VERSION 5.7 ;
BUSBITCHARS "[]" ;
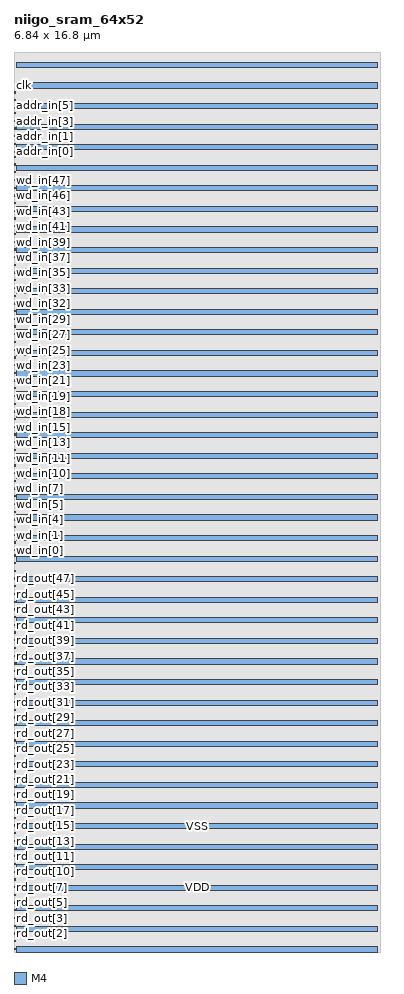
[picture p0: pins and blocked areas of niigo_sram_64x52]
MACRO niigo_sram_64x52
  FOREIGN niigo_sram_64x52 0 0 ;
  SYMMETRY X Y R90 ;
  SIZE 6.840 BY 16.800 ;
  CLASS BLOCK ;
  PIN rd_out[0]
    DIRECTION OUTPUT ;
    USE SIGNAL ;
    SHAPE ABUTMENT ;
    PORT
      LAYER M4 ;
      RECT 0.000 0.048 0.024 0.072 ;
    END
  END rd_out[0]
  PIN rd_out[1]
    DIRECTION OUTPUT ;
    USE SIGNAL ;
    SHAPE ABUTMENT ;
    PORT
      LAYER M4 ;
      RECT 0.000 0.192 0.024 0.216 ;
    END
  END rd_out[1]
  PIN rd_out[2]
    DIRECTION OUTPUT ;
    USE SIGNAL ;
    SHAPE ABUTMENT ;
    PORT
      LAYER M4 ;
      RECT 0.000 0.336 0.024 0.360 ;
    END
  END rd_out[2]
  PIN rd_out[3]
    DIRECTION OUTPUT ;
    USE SIGNAL ;
    SHAPE ABUTMENT ;
    PORT
      LAYER M4 ;
      RECT 0.000 0.480 0.024 0.504 ;
    END
  END rd_out[3]
  PIN rd_out[4]
    DIRECTION OUTPUT ;
    USE SIGNAL ;
    SHAPE ABUTMENT ;
    PORT
      LAYER M4 ;
      RECT 0.000 0.624 0.024 0.648 ;
    END
  END rd_out[4]
  PIN rd_out[5]
    DIRECTION OUTPUT ;
    USE SIGNAL ;
    SHAPE ABUTMENT ;
    PORT
      LAYER M4 ;
      RECT 0.000 0.768 0.024 0.792 ;
    END
  END rd_out[5]
  PIN rd_out[6]
    DIRECTION OUTPUT ;
    USE SIGNAL ;
    SHAPE ABUTMENT ;
    PORT
      LAYER M4 ;
      RECT 0.000 0.912 0.024 0.936 ;
    END
  END rd_out[6]
  PIN rd_out[7]
    DIRECTION OUTPUT ;
    USE SIGNAL ;
    SHAPE ABUTMENT ;
    PORT
      LAYER M4 ;
      RECT 0.000 1.056 0.024 1.080 ;
    END
  END rd_out[7]
  PIN rd_out[8]
    DIRECTION OUTPUT ;
    USE SIGNAL ;
    SHAPE ABUTMENT ;
    PORT
      LAYER M4 ;
      RECT 0.000 1.200 0.024 1.224 ;
    END
  END rd_out[8]
  PIN rd_out[9]
    DIRECTION OUTPUT ;
    USE SIGNAL ;
    SHAPE ABUTMENT ;
    PORT
      LAYER M4 ;
      RECT 0.000 1.344 0.024 1.368 ;
    END
  END rd_out[9]
  PIN rd_out[10]
    DIRECTION OUTPUT ;
    USE SIGNAL ;
    SHAPE ABUTMENT ;
    PORT
      LAYER M4 ;
      RECT 0.000 1.488 0.024 1.512 ;
    END
  END rd_out[10]
  PIN rd_out[11]
    DIRECTION OUTPUT ;
    USE SIGNAL ;
    SHAPE ABUTMENT ;
    PORT
      LAYER M4 ;
      RECT 0.000 1.632 0.024 1.656 ;
    END
  END rd_out[11]
  PIN rd_out[12]
    DIRECTION OUTPUT ;
    USE SIGNAL ;
    SHAPE ABUTMENT ;
    PORT
      LAYER M4 ;
      RECT 0.000 1.776 0.024 1.800 ;
    END
  END rd_out[12]
  PIN rd_out[13]
    DIRECTION OUTPUT ;
    USE SIGNAL ;
    SHAPE ABUTMENT ;
    PORT
      LAYER M4 ;
      RECT 0.000 1.920 0.024 1.944 ;
    END
  END rd_out[13]
  PIN rd_out[14]
    DIRECTION OUTPUT ;
    USE SIGNAL ;
    SHAPE ABUTMENT ;
    PORT
      LAYER M4 ;
      RECT 0.000 2.064 0.024 2.088 ;
    END
  END rd_out[14]
  PIN rd_out[15]
    DIRECTION OUTPUT ;
    USE SIGNAL ;
    SHAPE ABUTMENT ;
    PORT
      LAYER M4 ;
      RECT 0.000 2.208 0.024 2.232 ;
    END
  END rd_out[15]
  PIN rd_out[16]
    DIRECTION OUTPUT ;
    USE SIGNAL ;
    SHAPE ABUTMENT ;
    PORT
      LAYER M4 ;
      RECT 0.000 2.352 0.024 2.376 ;
    END
  END rd_out[16]
  PIN rd_out[17]
    DIRECTION OUTPUT ;
    USE SIGNAL ;
    SHAPE ABUTMENT ;
    PORT
      LAYER M4 ;
      RECT 0.000 2.496 0.024 2.520 ;
    END
  END rd_out[17]
  PIN rd_out[18]
    DIRECTION OUTPUT ;
    USE SIGNAL ;
    SHAPE ABUTMENT ;
    PORT
      LAYER M4 ;
      RECT 0.000 2.640 0.024 2.664 ;
    END
  END rd_out[18]
  PIN rd_out[19]
    DIRECTION OUTPUT ;
    USE SIGNAL ;
    SHAPE ABUTMENT ;
    PORT
      LAYER M4 ;
      RECT 0.000 2.784 0.024 2.808 ;
    END
  END rd_out[19]
  PIN rd_out[20]
    DIRECTION OUTPUT ;
    USE SIGNAL ;
    SHAPE ABUTMENT ;
    PORT
      LAYER M4 ;
      RECT 0.000 2.928 0.024 2.952 ;
    END
  END rd_out[20]
  PIN rd_out[21]
    DIRECTION OUTPUT ;
    USE SIGNAL ;
    SHAPE ABUTMENT ;
    PORT
      LAYER M4 ;
      RECT 0.000 3.072 0.024 3.096 ;
    END
  END rd_out[21]
  PIN rd_out[22]
    DIRECTION OUTPUT ;
    USE SIGNAL ;
    SHAPE ABUTMENT ;
    PORT
      LAYER M4 ;
      RECT 0.000 3.216 0.024 3.240 ;
    END
  END rd_out[22]
  PIN rd_out[23]
    DIRECTION OUTPUT ;
    USE SIGNAL ;
    SHAPE ABUTMENT ;
    PORT
      LAYER M4 ;
      RECT 0.000 3.360 0.024 3.384 ;
    END
  END rd_out[23]
  PIN rd_out[24]
    DIRECTION OUTPUT ;
    USE SIGNAL ;
    SHAPE ABUTMENT ;
    PORT
      LAYER M4 ;
      RECT 0.000 3.504 0.024 3.528 ;
    END
  END rd_out[24]
  PIN rd_out[25]
    DIRECTION OUTPUT ;
    USE SIGNAL ;
    SHAPE ABUTMENT ;
    PORT
      LAYER M4 ;
      RECT 0.000 3.648 0.024 3.672 ;
    END
  END rd_out[25]
  PIN rd_out[26]
    DIRECTION OUTPUT ;
    USE SIGNAL ;
    SHAPE ABUTMENT ;
    PORT
      LAYER M4 ;
      RECT 0.000 3.792 0.024 3.816 ;
    END
  END rd_out[26]
  PIN rd_out[27]
    DIRECTION OUTPUT ;
    USE SIGNAL ;
    SHAPE ABUTMENT ;
    PORT
      LAYER M4 ;
      RECT 0.000 3.936 0.024 3.960 ;
    END
  END rd_out[27]
  PIN rd_out[28]
    DIRECTION OUTPUT ;
    USE SIGNAL ;
    SHAPE ABUTMENT ;
    PORT
      LAYER M4 ;
      RECT 0.000 4.080 0.024 4.104 ;
    END
  END rd_out[28]
  PIN rd_out[29]
    DIRECTION OUTPUT ;
    USE SIGNAL ;
    SHAPE ABUTMENT ;
    PORT
      LAYER M4 ;
      RECT 0.000 4.224 0.024 4.248 ;
    END
  END rd_out[29]
  PIN rd_out[30]
    DIRECTION OUTPUT ;
    USE SIGNAL ;
    SHAPE ABUTMENT ;
    PORT
      LAYER M4 ;
      RECT 0.000 4.368 0.024 4.392 ;
    END
  END rd_out[30]
  PIN rd_out[31]
    DIRECTION OUTPUT ;
    USE SIGNAL ;
    SHAPE ABUTMENT ;
    PORT
      LAYER M4 ;
      RECT 0.000 4.512 0.024 4.536 ;
    END
  END rd_out[31]
  PIN rd_out[32]
    DIRECTION OUTPUT ;
    USE SIGNAL ;
    SHAPE ABUTMENT ;
    PORT
      LAYER M4 ;
      RECT 0.000 4.656 0.024 4.680 ;
    END
  END rd_out[32]
  PIN rd_out[33]
    DIRECTION OUTPUT ;
    USE SIGNAL ;
    SHAPE ABUTMENT ;
    PORT
      LAYER M4 ;
      RECT 0.000 4.800 0.024 4.824 ;
    END
  END rd_out[33]
  PIN rd_out[34]
    DIRECTION OUTPUT ;
    USE SIGNAL ;
    SHAPE ABUTMENT ;
    PORT
      LAYER M4 ;
      RECT 0.000 4.944 0.024 4.968 ;
    END
  END rd_out[34]
  PIN rd_out[35]
    DIRECTION OUTPUT ;
    USE SIGNAL ;
    SHAPE ABUTMENT ;
    PORT
      LAYER M4 ;
      RECT 0.000 5.088 0.024 5.112 ;
    END
  END rd_out[35]
  PIN rd_out[36]
    DIRECTION OUTPUT ;
    USE SIGNAL ;
    SHAPE ABUTMENT ;
    PORT
      LAYER M4 ;
      RECT 0.000 5.232 0.024 5.256 ;
    END
  END rd_out[36]
  PIN rd_out[37]
    DIRECTION OUTPUT ;
    USE SIGNAL ;
    SHAPE ABUTMENT ;
    PORT
      LAYER M4 ;
      RECT 0.000 5.376 0.024 5.400 ;
    END
  END rd_out[37]
  PIN rd_out[38]
    DIRECTION OUTPUT ;
    USE SIGNAL ;
    SHAPE ABUTMENT ;
    PORT
      LAYER M4 ;
      RECT 0.000 5.520 0.024 5.544 ;
    END
  END rd_out[38]
  PIN rd_out[39]
    DIRECTION OUTPUT ;
    USE SIGNAL ;
    SHAPE ABUTMENT ;
    PORT
      LAYER M4 ;
      RECT 0.000 5.664 0.024 5.688 ;
    END
  END rd_out[39]
  PIN rd_out[40]
    DIRECTION OUTPUT ;
    USE SIGNAL ;
    SHAPE ABUTMENT ;
    PORT
      LAYER M4 ;
      RECT 0.000 5.808 0.024 5.832 ;
    END
  END rd_out[40]
  PIN rd_out[41]
    DIRECTION OUTPUT ;
    USE SIGNAL ;
    SHAPE ABUTMENT ;
    PORT
      LAYER M4 ;
      RECT 0.000 5.952 0.024 5.976 ;
    END
  END rd_out[41]
  PIN rd_out[42]
    DIRECTION OUTPUT ;
    USE SIGNAL ;
    SHAPE ABUTMENT ;
    PORT
      LAYER M4 ;
      RECT 0.000 6.096 0.024 6.120 ;
    END
  END rd_out[42]
  PIN rd_out[43]
    DIRECTION OUTPUT ;
    USE SIGNAL ;
    SHAPE ABUTMENT ;
    PORT
      LAYER M4 ;
      RECT 0.000 6.240 0.024 6.264 ;
    END
  END rd_out[43]
  PIN rd_out[44]
    DIRECTION OUTPUT ;
    USE SIGNAL ;
    SHAPE ABUTMENT ;
    PORT
      LAYER M4 ;
      RECT 0.000 6.384 0.024 6.408 ;
    END
  END rd_out[44]
  PIN rd_out[45]
    DIRECTION OUTPUT ;
    USE SIGNAL ;
    SHAPE ABUTMENT ;
    PORT
      LAYER M4 ;
      RECT 0.000 6.528 0.024 6.552 ;
    END
  END rd_out[45]
  PIN rd_out[46]
    DIRECTION OUTPUT ;
    USE SIGNAL ;
    SHAPE ABUTMENT ;
    PORT
      LAYER M4 ;
      RECT 0.000 6.672 0.024 6.696 ;
    END
  END rd_out[46]
  PIN rd_out[47]
    DIRECTION OUTPUT ;
    USE SIGNAL ;
    SHAPE ABUTMENT ;
    PORT
      LAYER M4 ;
      RECT 0.000 6.816 0.024 6.840 ;
    END
  END rd_out[47]
  PIN rd_out[48]
    DIRECTION OUTPUT ;
    USE SIGNAL ;
    SHAPE ABUTMENT ;
    PORT
      LAYER M4 ;
      RECT 0.000 6.960 0.024 6.984 ;
    END
  END rd_out[48]
  PIN rd_out[49]
    DIRECTION OUTPUT ;
    USE SIGNAL ;
    SHAPE ABUTMENT ;
    PORT
      LAYER M4 ;
      RECT 0.000 7.104 0.024 7.128 ;
    END
  END rd_out[49]
  PIN rd_out[50]
    DIRECTION OUTPUT ;
    USE SIGNAL ;
    SHAPE ABUTMENT ;
    PORT
      LAYER M4 ;
      RECT 0.000 7.248 0.024 7.272 ;
    END
  END rd_out[50]
  PIN rd_out[51]
    DIRECTION OUTPUT ;
    USE SIGNAL ;
    SHAPE ABUTMENT ;
    PORT
      LAYER M4 ;
      RECT 0.000 7.392 0.024 7.416 ;
    END
  END rd_out[51]
  PIN wd_in[0]
    DIRECTION INPUT ;
    USE SIGNAL ;
    SHAPE ABUTMENT ;
    PORT
      LAYER M4 ;
      RECT 0.000 7.488 0.024 7.512 ;
    END
  END wd_in[0]
  PIN wd_in[1]
    DIRECTION INPUT ;
    USE SIGNAL ;
    SHAPE ABUTMENT ;
    PORT
      LAYER M4 ;
      RECT 0.000 7.632 0.024 7.656 ;
    END
  END wd_in[1]
  PIN wd_in[2]
    DIRECTION INPUT ;
    USE SIGNAL ;
    SHAPE ABUTMENT ;
    PORT
      LAYER M4 ;
      RECT 0.000 7.776 0.024 7.800 ;
    END
  END wd_in[2]
  PIN wd_in[3]
    DIRECTION INPUT ;
    USE SIGNAL ;
    SHAPE ABUTMENT ;
    PORT
      LAYER M4 ;
      RECT 0.000 7.920 0.024 7.944 ;
    END
  END wd_in[3]
  PIN wd_in[4]
    DIRECTION INPUT ;
    USE SIGNAL ;
    SHAPE ABUTMENT ;
    PORT
      LAYER M4 ;
      RECT 0.000 8.064 0.024 8.088 ;
    END
  END wd_in[4]
  PIN wd_in[5]
    DIRECTION INPUT ;
    USE SIGNAL ;
    SHAPE ABUTMENT ;
    PORT
      LAYER M4 ;
      RECT 0.000 8.208 0.024 8.232 ;
    END
  END wd_in[5]
  PIN wd_in[6]
    DIRECTION INPUT ;
    USE SIGNAL ;
    SHAPE ABUTMENT ;
    PORT
      LAYER M4 ;
      RECT 0.000 8.352 0.024 8.376 ;
    END
  END wd_in[6]
  PIN wd_in[7]
    DIRECTION INPUT ;
    USE SIGNAL ;
    SHAPE ABUTMENT ;
    PORT
      LAYER M4 ;
      RECT 0.000 8.496 0.024 8.520 ;
    END
  END wd_in[7]
  PIN wd_in[8]
    DIRECTION INPUT ;
    USE SIGNAL ;
    SHAPE ABUTMENT ;
    PORT
      LAYER M4 ;
      RECT 0.000 8.640 0.024 8.664 ;
    END
  END wd_in[8]
  PIN wd_in[9]
    DIRECTION INPUT ;
    USE SIGNAL ;
    SHAPE ABUTMENT ;
    PORT
      LAYER M4 ;
      RECT 0.000 8.784 0.024 8.808 ;
    END
  END wd_in[9]
  PIN wd_in[10]
    DIRECTION INPUT ;
    USE SIGNAL ;
    SHAPE ABUTMENT ;
    PORT
      LAYER M4 ;
      RECT 0.000 8.928 0.024 8.952 ;
    END
  END wd_in[10]
  PIN wd_in[11]
    DIRECTION INPUT ;
    USE SIGNAL ;
    SHAPE ABUTMENT ;
    PORT
      LAYER M4 ;
      RECT 0.000 9.072 0.024 9.096 ;
    END
  END wd_in[11]
  PIN wd_in[12]
    DIRECTION INPUT ;
    USE SIGNAL ;
    SHAPE ABUTMENT ;
    PORT
      LAYER M4 ;
      RECT 0.000 9.216 0.024 9.240 ;
    END
  END wd_in[12]
  PIN wd_in[13]
    DIRECTION INPUT ;
    USE SIGNAL ;
    SHAPE ABUTMENT ;
    PORT
      LAYER M4 ;
      RECT 0.000 9.360 0.024 9.384 ;
    END
  END wd_in[13]
  PIN wd_in[14]
    DIRECTION INPUT ;
    USE SIGNAL ;
    SHAPE ABUTMENT ;
    PORT
      LAYER M4 ;
      RECT 0.000 9.504 0.024 9.528 ;
    END
  END wd_in[14]
  PIN wd_in[15]
    DIRECTION INPUT ;
    USE SIGNAL ;
    SHAPE ABUTMENT ;
    PORT
      LAYER M4 ;
      RECT 0.000 9.648 0.024 9.672 ;
    END
  END wd_in[15]
  PIN wd_in[16]
    DIRECTION INPUT ;
    USE SIGNAL ;
    SHAPE ABUTMENT ;
    PORT
      LAYER M4 ;
      RECT 0.000 9.792 0.024 9.816 ;
    END
  END wd_in[16]
  PIN wd_in[17]
    DIRECTION INPUT ;
    USE SIGNAL ;
    SHAPE ABUTMENT ;
    PORT
      LAYER M4 ;
      RECT 0.000 9.936 0.024 9.960 ;
    END
  END wd_in[17]
  PIN wd_in[18]
    DIRECTION INPUT ;
    USE SIGNAL ;
    SHAPE ABUTMENT ;
    PORT
      LAYER M4 ;
      RECT 0.000 10.080 0.024 10.104 ;
    END
  END wd_in[18]
  PIN wd_in[19]
    DIRECTION INPUT ;
    USE SIGNAL ;
    SHAPE ABUTMENT ;
    PORT
      LAYER M4 ;
      RECT 0.000 10.224 0.024 10.248 ;
    END
  END wd_in[19]
  PIN wd_in[20]
    DIRECTION INPUT ;
    USE SIGNAL ;
    SHAPE ABUTMENT ;
    PORT
      LAYER M4 ;
      RECT 0.000 10.368 0.024 10.392 ;
    END
  END wd_in[20]
  PIN wd_in[21]
    DIRECTION INPUT ;
    USE SIGNAL ;
    SHAPE ABUTMENT ;
    PORT
      LAYER M4 ;
      RECT 0.000 10.512 0.024 10.536 ;
    END
  END wd_in[21]
  PIN wd_in[22]
    DIRECTION INPUT ;
    USE SIGNAL ;
    SHAPE ABUTMENT ;
    PORT
      LAYER M4 ;
      RECT 0.000 10.656 0.024 10.680 ;
    END
  END wd_in[22]
  PIN wd_in[23]
    DIRECTION INPUT ;
    USE SIGNAL ;
    SHAPE ABUTMENT ;
    PORT
      LAYER M4 ;
      RECT 0.000 10.800 0.024 10.824 ;
    END
  END wd_in[23]
  PIN wd_in[24]
    DIRECTION INPUT ;
    USE SIGNAL ;
    SHAPE ABUTMENT ;
    PORT
      LAYER M4 ;
      RECT 0.000 10.944 0.024 10.968 ;
    END
  END wd_in[24]
  PIN wd_in[25]
    DIRECTION INPUT ;
    USE SIGNAL ;
    SHAPE ABUTMENT ;
    PORT
      LAYER M4 ;
      RECT 0.000 11.088 0.024 11.112 ;
    END
  END wd_in[25]
  PIN wd_in[26]
    DIRECTION INPUT ;
    USE SIGNAL ;
    SHAPE ABUTMENT ;
    PORT
      LAYER M4 ;
      RECT 0.000 11.232 0.024 11.256 ;
    END
  END wd_in[26]
  PIN wd_in[27]
    DIRECTION INPUT ;
    USE SIGNAL ;
    SHAPE ABUTMENT ;
    PORT
      LAYER M4 ;
      RECT 0.000 11.376 0.024 11.400 ;
    END
  END wd_in[27]
  PIN wd_in[28]
    DIRECTION INPUT ;
    USE SIGNAL ;
    SHAPE ABUTMENT ;
    PORT
      LAYER M4 ;
      RECT 0.000 11.520 0.024 11.544 ;
    END
  END wd_in[28]
  PIN wd_in[29]
    DIRECTION INPUT ;
    USE SIGNAL ;
    SHAPE ABUTMENT ;
    PORT
      LAYER M4 ;
      RECT 0.000 11.664 0.024 11.688 ;
    END
  END wd_in[29]
  PIN wd_in[30]
    DIRECTION INPUT ;
    USE SIGNAL ;
    SHAPE ABUTMENT ;
    PORT
      LAYER M4 ;
      RECT 0.000 11.808 0.024 11.832 ;
    END
  END wd_in[30]
  PIN wd_in[31]
    DIRECTION INPUT ;
    USE SIGNAL ;
    SHAPE ABUTMENT ;
    PORT
      LAYER M4 ;
      RECT 0.000 11.952 0.024 11.976 ;
    END
  END wd_in[31]
  PIN wd_in[32]
    DIRECTION INPUT ;
    USE SIGNAL ;
    SHAPE ABUTMENT ;
    PORT
      LAYER M4 ;
      RECT 0.000 12.096 0.024 12.120 ;
    END
  END wd_in[32]
  PIN wd_in[33]
    DIRECTION INPUT ;
    USE SIGNAL ;
    SHAPE ABUTMENT ;
    PORT
      LAYER M4 ;
      RECT 0.000 12.240 0.024 12.264 ;
    END
  END wd_in[33]
  PIN wd_in[34]
    DIRECTION INPUT ;
    USE SIGNAL ;
    SHAPE ABUTMENT ;
    PORT
      LAYER M4 ;
      RECT 0.000 12.384 0.024 12.408 ;
    END
  END wd_in[34]
  PIN wd_in[35]
    DIRECTION INPUT ;
    USE SIGNAL ;
    SHAPE ABUTMENT ;
    PORT
      LAYER M4 ;
      RECT 0.000 12.528 0.024 12.552 ;
    END
  END wd_in[35]
  PIN wd_in[36]
    DIRECTION INPUT ;
    USE SIGNAL ;
    SHAPE ABUTMENT ;
    PORT
      LAYER M4 ;
      RECT 0.000 12.672 0.024 12.696 ;
    END
  END wd_in[36]
  PIN wd_in[37]
    DIRECTION INPUT ;
    USE SIGNAL ;
    SHAPE ABUTMENT ;
    PORT
      LAYER M4 ;
      RECT 0.000 12.816 0.024 12.840 ;
    END
  END wd_in[37]
  PIN wd_in[38]
    DIRECTION INPUT ;
    USE SIGNAL ;
    SHAPE ABUTMENT ;
    PORT
      LAYER M4 ;
      RECT 0.000 12.960 0.024 12.984 ;
    END
  END wd_in[38]
  PIN wd_in[39]
    DIRECTION INPUT ;
    USE SIGNAL ;
    SHAPE ABUTMENT ;
    PORT
      LAYER M4 ;
      RECT 0.000 13.104 0.024 13.128 ;
    END
  END wd_in[39]
  PIN wd_in[40]
    DIRECTION INPUT ;
    USE SIGNAL ;
    SHAPE ABUTMENT ;
    PORT
      LAYER M4 ;
      RECT 0.000 13.248 0.024 13.272 ;
    END
  END wd_in[40]
  PIN wd_in[41]
    DIRECTION INPUT ;
    USE SIGNAL ;
    SHAPE ABUTMENT ;
    PORT
      LAYER M4 ;
      RECT 0.000 13.392 0.024 13.416 ;
    END
  END wd_in[41]
  PIN wd_in[42]
    DIRECTION INPUT ;
    USE SIGNAL ;
    SHAPE ABUTMENT ;
    PORT
      LAYER M4 ;
      RECT 0.000 13.536 0.024 13.560 ;
    END
  END wd_in[42]
  PIN wd_in[43]
    DIRECTION INPUT ;
    USE SIGNAL ;
    SHAPE ABUTMENT ;
    PORT
      LAYER M4 ;
      RECT 0.000 13.680 0.024 13.704 ;
    END
  END wd_in[43]
  PIN wd_in[44]
    DIRECTION INPUT ;
    USE SIGNAL ;
    SHAPE ABUTMENT ;
    PORT
      LAYER M4 ;
      RECT 0.000 13.824 0.024 13.848 ;
    END
  END wd_in[44]
  PIN wd_in[45]
    DIRECTION INPUT ;
    USE SIGNAL ;
    SHAPE ABUTMENT ;
    PORT
      LAYER M4 ;
      RECT 0.000 13.968 0.024 13.992 ;
    END
  END wd_in[45]
  PIN wd_in[46]
    DIRECTION INPUT ;
    USE SIGNAL ;
    SHAPE ABUTMENT ;
    PORT
      LAYER M4 ;
      RECT 0.000 14.112 0.024 14.136 ;
    END
  END wd_in[46]
  PIN wd_in[47]
    DIRECTION INPUT ;
    USE SIGNAL ;
    SHAPE ABUTMENT ;
    PORT
      LAYER M4 ;
      RECT 0.000 14.256 0.024 14.280 ;
    END
  END wd_in[47]
  PIN wd_in[48]
    DIRECTION INPUT ;
    USE SIGNAL ;
    SHAPE ABUTMENT ;
    PORT
      LAYER M4 ;
      RECT 0.000 14.400 0.024 14.424 ;
    END
  END wd_in[48]
  PIN wd_in[49]
    DIRECTION INPUT ;
    USE SIGNAL ;
    SHAPE ABUTMENT ;
    PORT
      LAYER M4 ;
      RECT 0.000 14.544 0.024 14.568 ;
    END
  END wd_in[49]
  PIN wd_in[50]
    DIRECTION INPUT ;
    USE SIGNAL ;
    SHAPE ABUTMENT ;
    PORT
      LAYER M4 ;
      RECT 0.000 14.688 0.024 14.712 ;
    END
  END wd_in[50]
  PIN wd_in[51]
    DIRECTION INPUT ;
    USE SIGNAL ;
    SHAPE ABUTMENT ;
    PORT
      LAYER M4 ;
      RECT 0.000 14.832 0.024 14.856 ;
    END
  END wd_in[51]
  PIN addr_in[0]
    DIRECTION INPUT ;
    USE SIGNAL ;
    SHAPE ABUTMENT ;
    PORT
      LAYER M4 ;
      RECT 0.000 14.928 0.024 14.952 ;
    END
  END addr_in[0]
  PIN addr_in[1]
    DIRECTION INPUT ;
    USE SIGNAL ;
    SHAPE ABUTMENT ;
    PORT
      LAYER M4 ;
      RECT 0.000 15.072 0.024 15.096 ;
    END
  END addr_in[1]
  PIN addr_in[2]
    DIRECTION INPUT ;
    USE SIGNAL ;
    SHAPE ABUTMENT ;
    PORT
      LAYER M4 ;
      RECT 0.000 15.216 0.024 15.240 ;
    END
  END addr_in[2]
  PIN addr_in[3]
    DIRECTION INPUT ;
    USE SIGNAL ;
    SHAPE ABUTMENT ;
    PORT
      LAYER M4 ;
      RECT 0.000 15.360 0.024 15.384 ;
    END
  END addr_in[3]
  PIN addr_in[4]
    DIRECTION INPUT ;
    USE SIGNAL ;
    SHAPE ABUTMENT ;
    PORT
      LAYER M4 ;
      RECT 0.000 15.504 0.024 15.528 ;
    END
  END addr_in[4]
  PIN addr_in[5]
    DIRECTION INPUT ;
    USE SIGNAL ;
    SHAPE ABUTMENT ;
    PORT
      LAYER M4 ;
      RECT 0.000 15.648 0.024 15.672 ;
    END
  END addr_in[5]
  PIN we_in
    DIRECTION INPUT ;
    USE SIGNAL ;
    SHAPE ABUTMENT ;
    PORT
      LAYER M4 ;
      RECT 0.000 15.744 0.024 15.768 ;
    END
  END we_in
  PIN ce_in
    DIRECTION INPUT ;
    USE SIGNAL ;
    SHAPE ABUTMENT ;
    PORT
      LAYER M4 ;
      RECT 0.000 15.888 0.024 15.912 ;
    END
  END ce_in
  PIN clk
    DIRECTION INPUT ;
    USE SIGNAL ;
    SHAPE ABUTMENT ;
    PORT
      LAYER M4 ;
      RECT 0.000 16.032 0.024 16.056 ;
    END
  END clk
  PIN VSS
    DIRECTION INOUT ;
    USE GROUND ;
    PORT
      LAYER M4 ;
      RECT 0.048 0.000 6.792 0.096 ;
      RECT 0.048 0.768 6.792 0.864 ;
      RECT 0.048 1.536 6.792 1.632 ;
      RECT 0.048 2.304 6.792 2.400 ;
      RECT 0.048 3.072 6.792 3.168 ;
      RECT 0.048 3.840 6.792 3.936 ;
      RECT 0.048 4.608 6.792 4.704 ;
      RECT 0.048 5.376 6.792 5.472 ;
      RECT 0.048 6.144 6.792 6.240 ;
      RECT 0.048 6.912 6.792 7.008 ;
      RECT 0.048 7.680 6.792 7.776 ;
      RECT 0.048 8.448 6.792 8.544 ;
      RECT 0.048 9.216 6.792 9.312 ;
      RECT 0.048 9.984 6.792 10.080 ;
      RECT 0.048 10.752 6.792 10.848 ;
      RECT 0.048 11.520 6.792 11.616 ;
      RECT 0.048 12.288 6.792 12.384 ;
      RECT 0.048 13.056 6.792 13.152 ;
      RECT 0.048 13.824 6.792 13.920 ;
      RECT 0.048 14.592 6.792 14.688 ;
      RECT 0.048 15.360 6.792 15.456 ;
      RECT 0.048 16.128 6.792 16.224 ;
    END
  END VSS
  PIN VDD
    DIRECTION INOUT ;
    USE POWER ;
    PORT
      LAYER M4 ;
      RECT 0.048 0.384 6.792 0.480 ;
      RECT 0.048 1.152 6.792 1.248 ;
      RECT 0.048 1.920 6.792 2.016 ;
      RECT 0.048 2.688 6.792 2.784 ;
      RECT 0.048 3.456 6.792 3.552 ;
      RECT 0.048 4.224 6.792 4.320 ;
      RECT 0.048 4.992 6.792 5.088 ;
      RECT 0.048 5.760 6.792 5.856 ;
      RECT 0.048 6.528 6.792 6.624 ;
      RECT 0.048 7.296 6.792 7.392 ;
      RECT 0.048 8.064 6.792 8.160 ;
      RECT 0.048 8.832 6.792 8.928 ;
      RECT 0.048 9.600 6.792 9.696 ;
      RECT 0.048 10.368 6.792 10.464 ;
      RECT 0.048 11.136 6.792 11.232 ;
      RECT 0.048 11.904 6.792 12.000 ;
      RECT 0.048 12.672 6.792 12.768 ;
      RECT 0.048 13.440 6.792 13.536 ;
      RECT 0.048 14.208 6.792 14.304 ;
      RECT 0.048 14.976 6.792 15.072 ;
      RECT 0.048 15.744 6.792 15.840 ;
      RECT 0.048 16.512 6.792 16.608 ;
    END
  END VDD
  OBS
    LAYER M1 ;
    RECT 0 0 6.840 16.800 ;
    LAYER M2 ;
    RECT 0 0 6.840 16.800 ;
    LAYER M3 ;
    RECT 0 0 6.840 16.800 ;
    LAYER M4 ;
    RECT 0 0 6.840 16.800 ;
  END
END niigo_sram_64x52

END LIBRARY
